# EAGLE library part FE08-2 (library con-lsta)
FEMALE HEADER

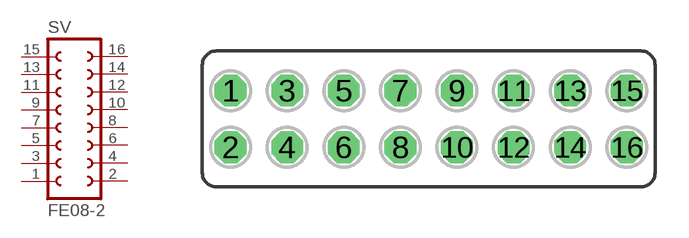
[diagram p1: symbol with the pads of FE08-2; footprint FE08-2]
Designator prefix SV

## FE08-2 (OC_FARNELL: unknown; OC_NEWARK: unknown)  [FE08-2]
1  1  pas
2  2  pas
3  3  pas
4  4  pas
5  5  pas
6  6  pas
7  7  pas
8  8  pas
9  9  pas
10  10  pas
11  11  pas
12  12  pas
13  13  pas
14  14  pas
15  15  pas
16  16  pas

## Footprint FE08-2 (pad centres in mm)
FEMALE HEADER
drill 0.914 octagon: 1 -8.89,1.27; 2 -8.89,-1.27; 3 -6.35,1.27; 4 -6.35,-1.27; 5 -3.81,1.27; 6 -3.81,-1.27; 7 -1.27,1.27; 8 -1.27,-1.27; 9 1.27,1.27; 10 1.27,-1.27; 11 3.81,1.27; 12 3.81,-1.27; 13 6.35,1.27; 14 6.35,-1.27; 15 8.89,1.27; 16 8.89,-1.27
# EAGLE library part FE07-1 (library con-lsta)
FEMALE HEADER

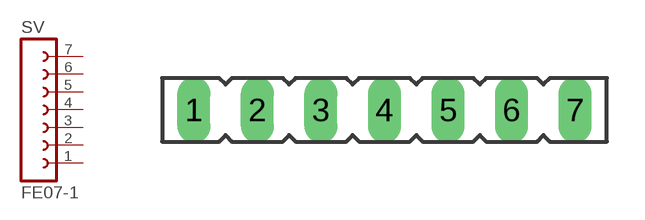
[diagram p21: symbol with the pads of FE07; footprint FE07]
Designator prefix SV

## FE07-1 (OC_FARNELL: unknown; OC_NEWARK: unknown)  [FE07]
1  1  pas
2  2  pas
3  3  pas
4  4  pas
5  5  pas
6  6  pas
7  7  pas

## Footprint FE07 (pad centres in mm)
FEMALE HEADER
drill 0.813 long: 1 -7.62,0; 2 -5.08,0; 3 -2.54,0; 4 0,0; 5 2.54,0; 6 5.08,0; 7 7.62,0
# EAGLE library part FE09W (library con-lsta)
FEMALE HEADER

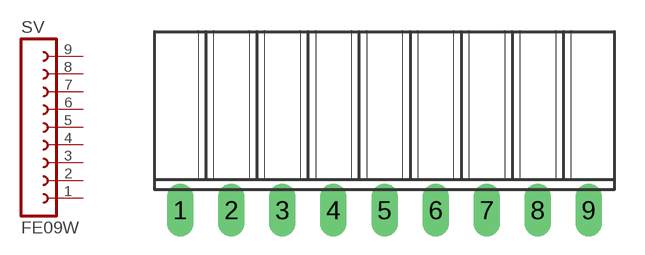
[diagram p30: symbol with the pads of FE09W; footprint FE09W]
Designator prefix SV

## FE09W (OC_FARNELL: unknown; OC_NEWARK: unknown)  [FE09W]
1  1  pas
2  2  pas
3  3  pas
4  4  pas
5  5  pas
6  6  pas
7  7  pas
8  8  pas
9  9  pas

## Footprint FE09W (pad centres in mm)
FEMALE HEADER
drill 0.813 long: 1 -10.16,0; 2 -7.62,0; 3 -5.08,0; 4 -2.54,0; 5 0,0; 6 2.54,0; 7 5.08,0; 8 7.62,0; 9 10.16,0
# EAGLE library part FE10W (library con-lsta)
FEMALE HEADER

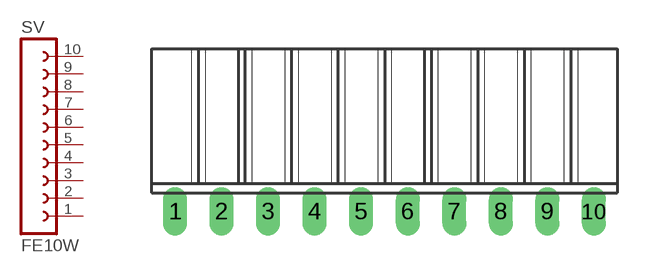
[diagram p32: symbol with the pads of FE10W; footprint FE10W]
Designator prefix SV

## FE10W (OC_FARNELL: unknown; OC_NEWARK: unknown)  [FE10W]
1  1  pas
2  2  pas
3  3  pas
4  4  pas
5  5  pas
6  6  pas
7  7  pas
8  8  pas
9  9  pas
10  10  pas

## Footprint FE10W (pad centres in mm)
FEMALE HEADER
drill 0.813 long: 1 -11.43,0; 2 -8.89,0; 3 -6.35,0; 4 -3.81,0; 5 -1.27,0; 6 1.27,0; 7 3.81,0; 8 6.35,0; 9 8.89,0; 10 11.43,0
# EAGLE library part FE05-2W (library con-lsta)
FEMALE HEADER

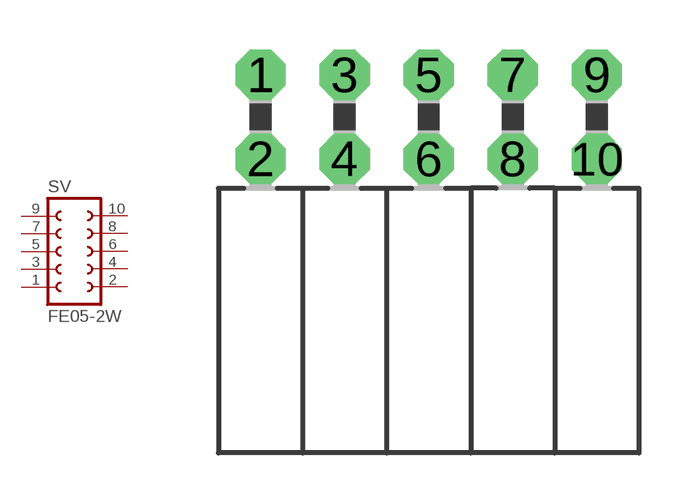
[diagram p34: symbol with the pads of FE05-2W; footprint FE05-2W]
Designator prefix SV

## FE05-2W (OC_FARNELL: unknown; OC_NEWARK: unknown)  [FE05-2W]
1  1  pas
2  2  pas
3  3  pas
4  4  pas
5  5  pas
6  6  pas
7  7  pas
8  8  pas
9  9  pas
10  10  pas

## Footprint FE05-2W (pad centres in mm)
FEMALE HEADER
drill 1.016 octagon: 1 -5.08,1.27; 2 -5.08,-1.27; 3 -2.54,1.27; 4 -2.54,-1.27; 5 0,1.27; 6 0,-1.27; 7 2.54,1.27; 8 2.54,-1.27; 9 5.08,1.27; 10 5.08,-1.27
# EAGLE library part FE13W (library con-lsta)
FEMALE HEADER

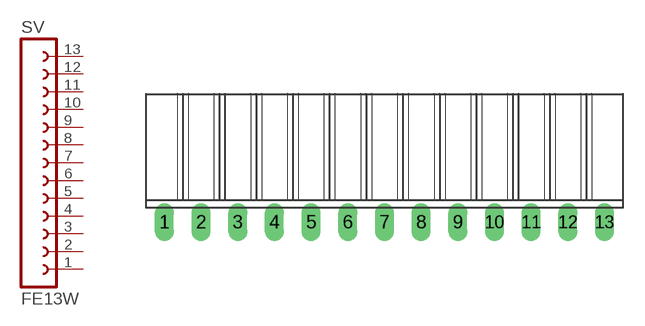
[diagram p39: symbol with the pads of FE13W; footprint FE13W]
Designator prefix SV

## FE13W (OC_FARNELL: unknown; OC_NEWARK: unknown)  [FE13W]
1  1  pas
2  2  pas
3  3  pas
4  4  pas
5  5  pas
6  6  pas
7  7  pas
8  8  pas
9  9  pas
10  10  pas
11  11  pas
12  12  pas
13  13  pas

## Footprint FE13W (pad centres in mm)
FEMALE HEADER
drill 0.813 long: 1 -15.24,0; 2 -12.7,0; 3 -10.16,0; 4 -7.62,0; 5 -5.08,0; 6 -2.54,0; 7 0,0; 8 2.54,0; 9 5.08,0; 10 7.62,0; 11 10.16,0; 12 12.7,0; 13 15.24,0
